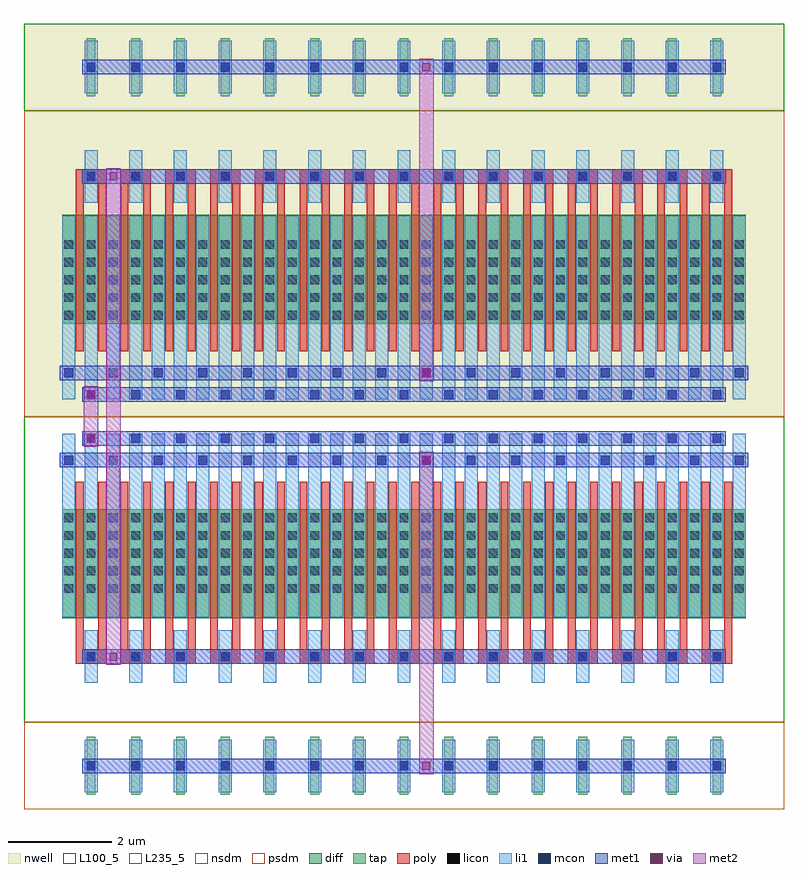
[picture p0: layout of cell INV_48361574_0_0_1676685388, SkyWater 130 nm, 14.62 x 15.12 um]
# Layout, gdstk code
import gdstk
lib = gdstk.Library(unit=1e-6, precision=1e-09)
def R(c, l, rs):  # rectangles x0, y0, x1, y1
    for r in rs: c.add(gdstk.rectangle(r[:2], r[2:], *l))
def A(c, l, x, y, w, h, nx, ny, dx, dy):  # array of equal rectangles
    R(c, l, [(x+i*dx, y+j*dy, x+i*dx+w, y+j*dy+h) for i in range(nx) for j in range(ny)])
def P(c, l, *ps):  # polygons
    for p in ps: c.add(gdstk.Polygon(p, *l))
nwell = (64, 20)
diff = (65, 20)
tap = (65, 44)
poly = (66, 20)
licon = (66, 44)
li1 = (67, 20)
mcon = (67, 44)
met1 = (68, 20)
via = (68, 44)
met2 = (69, 20)
nsdm = (93, 44)
psdm = (94, 20)
L100_5 = (100, 5)
L235_5 = (235, 5)

nmos_s_66195852_x15_y1_1 = lib.new_cell('NMOS_S_66195852_X15_Y1_1676685378_1676685388')
R(nmos_s_66195852_x15_y1_1, diff, [(0.735,1.785,13.885,3.885)])
A(nmos_s_66195852_x15_y1_1, tap, 1.205, 6.16, 0.17, 1.12, 15, 1, 0.86, 0)
A(nmos_s_66195852_x15_y1_1, poly, 1, 1.26, 0.15, 3.36, 30, 1, 0.43, 0)
A(nmos_s_66195852_x15_y1_1, poly, 1, 4.485, 0.58, 0.27, 15, 1, 0.86, 0)
A(nmos_s_66195852_x15_y1_1, licon, 0.775, 1.865, 0.17, 0.17, 3, 5, 0.43, 0.34)
A(nmos_s_66195852_x15_y1_1, licon, 1.635, 1.865, 0.17, 0.17, 3, 5, 0.43, 0.34)
A(nmos_s_66195852_x15_y1_1, licon, 2.495, 1.865, 0.17, 0.17, 3, 5, 0.43, 0.34)
A(nmos_s_66195852_x15_y1_1, licon, 3.355, 1.865, 0.17, 0.17, 3, 5, 0.43, 0.34)
A(nmos_s_66195852_x15_y1_1, licon, 4.215, 1.865, 0.17, 0.17, 3, 5, 0.43, 0.34)
A(nmos_s_66195852_x15_y1_1, licon, 5.075, 1.865, 0.17, 0.17, 3, 5, 0.43, 0.34)
A(nmos_s_66195852_x15_y1_1, licon, 5.935, 1.865, 0.17, 0.17, 3, 5, 0.43, 0.34)
A(nmos_s_66195852_x15_y1_1, licon, 6.795, 1.865, 0.17, 0.17, 3, 5, 0.43, 0.34)
A(nmos_s_66195852_x15_y1_1, licon, 7.655, 1.865, 0.17, 0.17, 3, 5, 0.43, 0.34)
A(nmos_s_66195852_x15_y1_1, licon, 8.515, 1.865, 0.17, 0.17, 3, 5, 0.43, 0.34)
A(nmos_s_66195852_x15_y1_1, licon, 9.375, 1.865, 0.17, 0.17, 3, 5, 0.43, 0.34)
A(nmos_s_66195852_x15_y1_1, licon, 10.235, 1.865, 0.17, 0.17, 3, 5, 0.43, 0.34)
A(nmos_s_66195852_x15_y1_1, licon, 11.095, 1.865, 0.17, 0.17, 3, 5, 0.43, 0.34)
A(nmos_s_66195852_x15_y1_1, licon, 11.955, 1.865, 0.17, 0.17, 3, 5, 0.43, 0.34)
A(nmos_s_66195852_x15_y1_1, licon, 12.815, 1.865, 0.17, 0.17, 3, 5, 0.43, 0.34)
A(nmos_s_66195852_x15_y1_1, licon, 1.205, 4.535, 0.17, 0.17, 15, 2, 0.86, 2.1)
A(nmos_s_66195852_x15_y1_1, li1, 0.735, 0.335, 0.25, 3.53, 31, 1, 0.43, 0)
A(nmos_s_66195852_x15_y1_1, li1, 1.165, 4.115, 0.25, 1.01, 15, 2, 0.86, 2.1)
A(nmos_s_66195852_x15_y1_1, mcon, 1.205, 0.335, 0.17, 0.17, 15, 2, 0.86, 4.2)
A(nmos_s_66195852_x15_y1_1, mcon, 0.775, 0.755, 0.17, 0.17, 16, 1, 0.86, 0)
A(nmos_s_66195852_x15_y1_1, mcon, 1.205, 6.635, 0.17, 0.17, 15, 1, 0.86, 0)
R(nmos_s_66195852_x15_y1_1, met1, [(1.12,0.28,13.5,0.56), (0.69,0.7,13.93,0.98), (1.12,4.48,13.5,4.76), (1.12,6.58,13.5,6.86)])
R(nmos_s_66195852_x15_y1_1, via, [(7.665,0.765,7.815,0.915), (7.665,6.645,7.815,6.795)])
R(nmos_s_66195852_x15_y1_1, met2, [(7.6,0.68,7.88,6.88)])
R(nmos_s_66195852_x15_y1_1, nsdm, [(0,0,14.62,5.88)])
R(nmos_s_66195852_x15_y1_1, psdm, [(0,5.88,14.62,7.56)])
R(nmos_s_66195852_x15_y1_1, L100_5, [(0,0,14.62,7.56)])

pmos_s_32003889_x15_y1_1 = lib.new_cell('PMOS_S_32003889_X15_Y1_1676685379_1676685388')
R(pmos_s_32003889_x15_y1_1, nwell, [(0,0,14.62,7.56)])
R(pmos_s_32003889_x15_y1_1, diff, [(0.735,1.785,13.885,3.885)])
A(pmos_s_32003889_x15_y1_1, tap, 1.205, 6.16, 0.17, 1.12, 15, 1, 0.86, 0)
A(pmos_s_32003889_x15_y1_1, poly, 1, 1.26, 0.15, 3.36, 30, 1, 0.43, 0)
A(pmos_s_32003889_x15_y1_1, poly, 1, 4.485, 0.58, 0.27, 15, 1, 0.86, 0)
A(pmos_s_32003889_x15_y1_1, licon, 0.775, 1.865, 0.17, 0.17, 3, 5, 0.43, 0.34)
A(pmos_s_32003889_x15_y1_1, licon, 1.635, 1.865, 0.17, 0.17, 3, 5, 0.43, 0.34)
A(pmos_s_32003889_x15_y1_1, licon, 2.495, 1.865, 0.17, 0.17, 3, 5, 0.43, 0.34)
A(pmos_s_32003889_x15_y1_1, licon, 3.355, 1.865, 0.17, 0.17, 3, 5, 0.43, 0.34)
A(pmos_s_32003889_x15_y1_1, licon, 4.215, 1.865, 0.17, 0.17, 3, 5, 0.43, 0.34)
A(pmos_s_32003889_x15_y1_1, licon, 5.075, 1.865, 0.17, 0.17, 3, 5, 0.43, 0.34)
A(pmos_s_32003889_x15_y1_1, licon, 5.935, 1.865, 0.17, 0.17, 3, 5, 0.43, 0.34)
A(pmos_s_32003889_x15_y1_1, licon, 6.795, 1.865, 0.17, 0.17, 3, 5, 0.43, 0.34)
A(pmos_s_32003889_x15_y1_1, licon, 7.655, 1.865, 0.17, 0.17, 3, 5, 0.43, 0.34)
A(pmos_s_32003889_x15_y1_1, licon, 8.515, 1.865, 0.17, 0.17, 3, 5, 0.43, 0.34)
A(pmos_s_32003889_x15_y1_1, licon, 9.375, 1.865, 0.17, 0.17, 3, 5, 0.43, 0.34)
A(pmos_s_32003889_x15_y1_1, licon, 10.235, 1.865, 0.17, 0.17, 3, 5, 0.43, 0.34)
A(pmos_s_32003889_x15_y1_1, licon, 11.095, 1.865, 0.17, 0.17, 3, 5, 0.43, 0.34)
A(pmos_s_32003889_x15_y1_1, licon, 11.955, 1.865, 0.17, 0.17, 3, 5, 0.43, 0.34)
A(pmos_s_32003889_x15_y1_1, licon, 12.815, 1.865, 0.17, 0.17, 3, 5, 0.43, 0.34)
A(pmos_s_32003889_x15_y1_1, licon, 1.205, 4.535, 0.17, 0.17, 15, 2, 0.86, 2.1)
A(pmos_s_32003889_x15_y1_1, li1, 0.735, 0.335, 0.25, 3.53, 31, 1, 0.43, 0)
A(pmos_s_32003889_x15_y1_1, li1, 1.165, 4.115, 0.25, 1.01, 15, 2, 0.86, 2.1)
A(pmos_s_32003889_x15_y1_1, mcon, 1.205, 0.335, 0.17, 0.17, 15, 2, 0.86, 4.2)
A(pmos_s_32003889_x15_y1_1, mcon, 0.775, 0.755, 0.17, 0.17, 16, 1, 0.86, 0)
A(pmos_s_32003889_x15_y1_1, mcon, 1.205, 6.635, 0.17, 0.17, 15, 1, 0.86, 0)
R(pmos_s_32003889_x15_y1_1, met1, [(1.12,0.28,13.5,0.56), (0.69,0.7,13.93,0.98), (1.12,4.48,13.5,4.76), (1.12,6.58,13.5,6.86)])
R(pmos_s_32003889_x15_y1_1, via, [(7.665,0.765,7.815,0.915), (7.665,6.645,7.815,6.795)])
R(pmos_s_32003889_x15_y1_1, met2, [(7.6,0.68,7.88,6.88)])
R(pmos_s_32003889_x15_y1_1, nsdm, [(0,5.88,14.62,7.56)])
R(pmos_s_32003889_x15_y1_1, psdm, [(0,0,14.62,5.88)])
R(pmos_s_32003889_x15_y1_1, L100_5, [(0,0,14.62,7.56)])

inv_48361574_0_0_1676685 = lib.new_cell('INV_48361574_0_0_1676685388')
R(inv_48361574_0_0_1676685, met1, [(1.56,2.8,1.88,3.08), (1.56,2.8,1.88,3.08), (1.13,7,1.45,7.28), (1.13,7,1.45,7.28), (1.13,7.84,1.45,8.12), (1.13,7.84,1.45,8.12), (1.56,12.04,1.88,12.32), (1.56,12.04,1.88,12.32)])
P(inv_48361574_0_0_1676685, met1, [(0,0),(0,0),(0,0),(0,0)],
  [(0,0),(0,0),(0,0),(0,0)],
  [(0,0),(0,0),(0,0),(0,0)],
  [(0,0),(0,0),(0,0),(0,0)])
R(inv_48361574_0_0_1676685, via, [(1.645,2.865,1.795,3.015), (1.645,2.865,1.795,3.015), (1.215,7.065,1.365,7.215), (1.215,7.065,1.365,7.215), (1.215,7.905,1.365,8.055), (1.215,7.905,1.365,8.055), (1.645,12.105,1.795,12.255), (1.645,12.105,1.795,12.255)])
R(inv_48361574_0_0_1676685, met2, [(1.58,2.78,1.86,3.1), (1.58,2.78,1.86,3.1), (1.58,2.94,1.86,12.18), (1.15,6.98,1.43,7.3), (1.15,6.98,1.43,7.3), (1.15,7.14,1.43,7.98), (1.15,7.82,1.43,8.14), (1.15,7.82,1.43,8.14), (1.58,12.02,1.86,12.34), (1.58,12.02,1.86,12.34)])
P(inv_48361574_0_0_1676685, met2, [(0,0),(0,0),(0,0),(0,0)],
  [(0,0),(0,0),(0,0),(0,0)])
R(inv_48361574_0_0_1676685, L235_5, [(0,0,14.62,15.12)])
inv_48361574_0_0_1676685.add(gdstk.Reference(nmos_s_66195852_x15_y1_1, (0,7.56), x_reflection=True))
inv_48361574_0_0_1676685.add(gdstk.Reference(pmos_s_32003889_x15_y1_1, (0,7.56)))

lib.write_gds('INV_48361574_0_0_1676685388.gds')
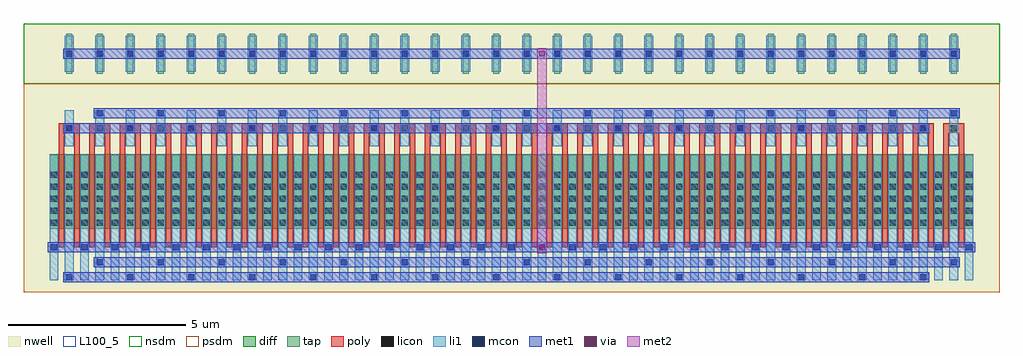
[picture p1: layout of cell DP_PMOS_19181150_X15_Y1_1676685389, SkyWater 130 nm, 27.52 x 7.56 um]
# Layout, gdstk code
import gdstk
lib = gdstk.Library(unit=1e-6, precision=1e-09)
def R(c, l, rs):  # rectangles x0, y0, x1, y1
    for r in rs: c.add(gdstk.rectangle(r[:2], r[2:], *l))
def A(c, l, x, y, w, h, nx, ny, dx, dy):  # array of equal rectangles
    R(c, l, [(x+i*dx, y+j*dy, x+i*dx+w, y+j*dy+h) for i in range(nx) for j in range(ny)])
nwell = (64, 20)
diff = (65, 20)
tap = (65, 44)
poly = (66, 20)
licon = (66, 44)
li1 = (67, 20)
mcon = (67, 44)
met1 = (68, 20)
via = (68, 44)
met2 = (69, 20)
nsdm = (93, 44)
psdm = (94, 20)
L100_5 = (100, 5)

dp_pmos_19181150_x15_y1_ = lib.new_cell('DP_PMOS_19181150_X15_Y1_1676685389')
R(dp_pmos_19181150_x15_y1_, nwell, [(0,0,27.52,7.56)])
R(dp_pmos_19181150_x15_y1_, diff, [(0.735,1.785,26.785,3.885)])
A(dp_pmos_19181150_x15_y1_, tap, 1.205, 6.16, 0.17, 1.12, 30, 1, 0.86, 0)
A(dp_pmos_19181150_x15_y1_, poly, 1, 1.26, 0.15, 3.36, 60, 1, 0.43, 0)
A(dp_pmos_19181150_x15_y1_, poly, 1, 4.485, 0.58, 0.27, 30, 1, 0.86, 0)
A(dp_pmos_19181150_x15_y1_, licon, 0.775, 1.865, 0.17, 0.17, 3, 5, 0.43, 0.34)
A(dp_pmos_19181150_x15_y1_, licon, 1.635, 1.865, 0.17, 0.17, 3, 5, 0.43, 0.34)
A(dp_pmos_19181150_x15_y1_, licon, 2.495, 1.865, 0.17, 0.17, 3, 5, 0.43, 0.34)
A(dp_pmos_19181150_x15_y1_, licon, 3.355, 1.865, 0.17, 0.17, 3, 5, 0.43, 0.34)
A(dp_pmos_19181150_x15_y1_, licon, 4.215, 1.865, 0.17, 0.17, 3, 5, 0.43, 0.34)
A(dp_pmos_19181150_x15_y1_, licon, 5.075, 1.865, 0.17, 0.17, 3, 5, 0.43, 0.34)
A(dp_pmos_19181150_x15_y1_, licon, 5.935, 1.865, 0.17, 0.17, 3, 5, 0.43, 0.34)
A(dp_pmos_19181150_x15_y1_, licon, 6.795, 1.865, 0.17, 0.17, 3, 5, 0.43, 0.34)
A(dp_pmos_19181150_x15_y1_, licon, 7.655, 1.865, 0.17, 0.17, 3, 5, 0.43, 0.34)
A(dp_pmos_19181150_x15_y1_, licon, 8.515, 1.865, 0.17, 0.17, 3, 5, 0.43, 0.34)
A(dp_pmos_19181150_x15_y1_, licon, 9.375, 1.865, 0.17, 0.17, 3, 5, 0.43, 0.34)
A(dp_pmos_19181150_x15_y1_, licon, 10.235, 1.865, 0.17, 0.17, 3, 5, 0.43, 0.34)
A(dp_pmos_19181150_x15_y1_, licon, 11.095, 1.865, 0.17, 0.17, 3, 5, 0.43, 0.34)
A(dp_pmos_19181150_x15_y1_, licon, 11.955, 1.865, 0.17, 0.17, 3, 5, 0.43, 0.34)
A(dp_pmos_19181150_x15_y1_, licon, 12.815, 1.865, 0.17, 0.17, 3, 5, 0.43, 0.34)
A(dp_pmos_19181150_x15_y1_, licon, 13.675, 1.865, 0.17, 0.17, 3, 5, 0.43, 0.34)
A(dp_pmos_19181150_x15_y1_, licon, 14.535, 1.865, 0.17, 0.17, 3, 5, 0.43, 0.34)
A(dp_pmos_19181150_x15_y1_, licon, 15.395, 1.865, 0.17, 0.17, 3, 5, 0.43, 0.34)
A(dp_pmos_19181150_x15_y1_, licon, 16.255, 1.865, 0.17, 0.17, 3, 5, 0.43, 0.34)
A(dp_pmos_19181150_x15_y1_, licon, 17.115, 1.865, 0.17, 0.17, 3, 5, 0.43, 0.34)
A(dp_pmos_19181150_x15_y1_, licon, 17.975, 1.865, 0.17, 0.17, 3, 5, 0.43, 0.34)
A(dp_pmos_19181150_x15_y1_, licon, 18.835, 1.865, 0.17, 0.17, 3, 5, 0.43, 0.34)
A(dp_pmos_19181150_x15_y1_, licon, 19.695, 1.865, 0.17, 0.17, 3, 5, 0.43, 0.34)
A(dp_pmos_19181150_x15_y1_, licon, 20.555, 1.865, 0.17, 0.17, 3, 5, 0.43, 0.34)
A(dp_pmos_19181150_x15_y1_, licon, 21.415, 1.865, 0.17, 0.17, 3, 5, 0.43, 0.34)
A(dp_pmos_19181150_x15_y1_, licon, 22.275, 1.865, 0.17, 0.17, 3, 5, 0.43, 0.34)
A(dp_pmos_19181150_x15_y1_, licon, 23.135, 1.865, 0.17, 0.17, 3, 5, 0.43, 0.34)
A(dp_pmos_19181150_x15_y1_, licon, 23.995, 1.865, 0.17, 0.17, 3, 5, 0.43, 0.34)
A(dp_pmos_19181150_x15_y1_, licon, 24.855, 1.865, 0.17, 0.17, 3, 5, 0.43, 0.34)
A(dp_pmos_19181150_x15_y1_, licon, 25.715, 1.865, 0.17, 0.17, 3, 5, 0.43, 0.34)
A(dp_pmos_19181150_x15_y1_, licon, 1.205, 4.535, 0.17, 0.17, 30, 2, 0.86, 2.1)
A(dp_pmos_19181150_x15_y1_, li1, 0.735, 0.335, 0.25, 3.53, 61, 1, 0.43, 0)
A(dp_pmos_19181150_x15_y1_, li1, 1.165, 4.115, 0.25, 1.01, 30, 2, 0.86, 2.1)
A(dp_pmos_19181150_x15_y1_, mcon, 1.205, 0.335, 0.17, 0.17, 15, 2, 1.72, 4.2)
A(dp_pmos_19181150_x15_y1_, mcon, 2.065, 0.755, 0.17, 0.17, 15, 2, 1.72, 4.2)
A(dp_pmos_19181150_x15_y1_, mcon, 0.775, 1.175, 0.17, 0.17, 31, 1, 0.86, 0)
A(dp_pmos_19181150_x15_y1_, mcon, 1.205, 6.635, 0.17, 0.17, 30, 1, 0.86, 0)
R(dp_pmos_19181150_x15_y1_, met1, [(1.12,0.28,25.54,0.56), (1.98,0.7,26.4,0.98), (0.69,1.12,26.83,1.4), (1.12,4.48,25.54,4.76), (1.98,4.9,26.4,5.18), (1.12,6.58,26.4,6.86)])
R(dp_pmos_19181150_x15_y1_, via, [(14.545,1.185,14.695,1.335), (14.545,6.645,14.695,6.795)])
R(dp_pmos_19181150_x15_y1_, met2, [(14.48,1.1,14.76,6.88)])
R(dp_pmos_19181150_x15_y1_, nsdm, [(0,5.88,27.52,7.56)])
R(dp_pmos_19181150_x15_y1_, psdm, [(0,0,27.52,5.88)])
R(dp_pmos_19181150_x15_y1_, L100_5, [(0,0,27.52,7.56)])

lib.write_gds('DP_PMOS_19181150_X15_Y1_1676685389.gds')
